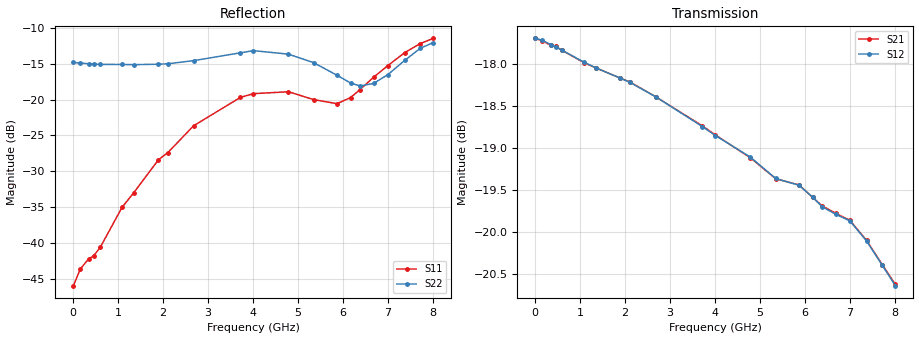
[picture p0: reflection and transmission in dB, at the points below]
! DEVICE ID: PE43712
! File Path: z:\PE43713\PE43713_CHAR_NOM_04292014\AMB\3p300\LS_ATT_16p50dB\PE43713_AMB_3p300V_3p000V_0p000V_LS_ATT_16p50dB_S2P_SN_10_A0139A.s2p
! Serial: 10
! Lot: A0139A
! Temp: 25C
! VDD: 3.300
! VSS: 0.000
! Control_Hi: 3.000
! Control_Lo: 0.000
! Attenuation Step: 16.50dB
! Port 1: RF1
! Port 2: RF2
! ThroughPath:1-2
! IDD: 0.0001462105
! ISS: -1.619e-007
#  Hz  S  RI  R  50
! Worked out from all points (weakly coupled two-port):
!   801 points, 10 MHz to 8.01 GHz, reference 50 ohm
!   highest |S21| = -17.70 dB at 10 MHz (marker M1); lowest = -20.6 dB at 8.01 GHz (marker M2)
!   lowest |S11| = -45.9 dB at 10 MHz (marker M3), VSWR 1.01, Z = 50.5 + j0.0422 ohm
!   |S11| at or under -10 dB: start of sweep to end of sweep
!   |S22| runs from -18.2 to -12.1 dB; largest |S21 - S12| = 0.00047
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1e7  0.00505 0.000417  0.1303 -0.000648  0.1303 -0.000601  -0.1812 0.00115
1.6e8  0.00616 0.00237  0.1296 -0.00851  0.1297 -0.0085  -0.179 0.0113
3.5e8  0.00667 0.00406  0.1278 -0.018  0.128 -0.0176  -0.1764 0.0213
4.6e8  0.00621 0.00532  0.1267 -0.0235  0.1267 -0.0234  -0.1745 0.0275
6.1e8  0.00568 0.00751  0.1245 -0.0304  0.1245 -0.0304  -0.1717 0.0364
1.09e9  0.0048 0.0171  0.1153 -0.0509  0.1154 -0.0509  -0.1636 0.0634
1.35e9  0.00584 0.0217  0.1094 -0.0608  0.1094 -0.0608  -0.1576 0.076
1.9e9  0.0116 0.0363  0.0942 -0.0797  0.0942 -0.0797  -0.1397 0.1073
2.11e9  0.0141 0.0404  0.0875 -0.0861  0.0875 -0.086  -0.1336 0.1167
2.68e9  0.0255 0.0605  0.0672 -0.0998  0.0672 -0.0998  -0.1085 0.1518
3.72e9  0.032 0.0984  0.0258 -0.1127  0.0257 -0.1126  -0.0835 0.1943
4.01e9  0.0321 0.1051  0.0142 -0.1133  0.0142 -0.1132  -0.0826 0.2028
4.79e9  0.0327 0.1085  -0.0153 -0.1096  -0.0153 -0.1097  -0.0692 0.1951
5.35e9  0.0438 0.0898  -0.0341 -0.102  -0.0342 -0.102  -0.0535 0.1724
5.87e9  0.0636 0.0687  -0.0509 -0.0937  -0.0508 -0.0937  -0.0161 0.1466
6.17e9  0.0822 0.0626  -0.0601 -0.0859  -0.0599 -0.0861  0.0135 0.1296
6.38e9  0.0999 0.0615  -0.0649 -0.0808  -0.0647 -0.0808  0.0374 0.1187
6.68e9  0.1297 0.06  -0.0721 -0.073  -0.0719 -0.073  0.0741 0.1061
7e9  0.1604 0.0634  -0.0793 -0.0635  -0.0792 -0.0635  0.1088 0.102
7.37e9  0.1996 0.0709  -0.0851 -0.0503  -0.085 -0.0503  0.1528 0.1079
7.72e9  0.2322 0.0796  -0.0874 -0.0388  -0.0873 -0.0388  0.1938 0.1188
8.01e9  0.2509 0.0901  -0.0881 -0.03  -0.0879 -0.0301  0.2155 0.1257
